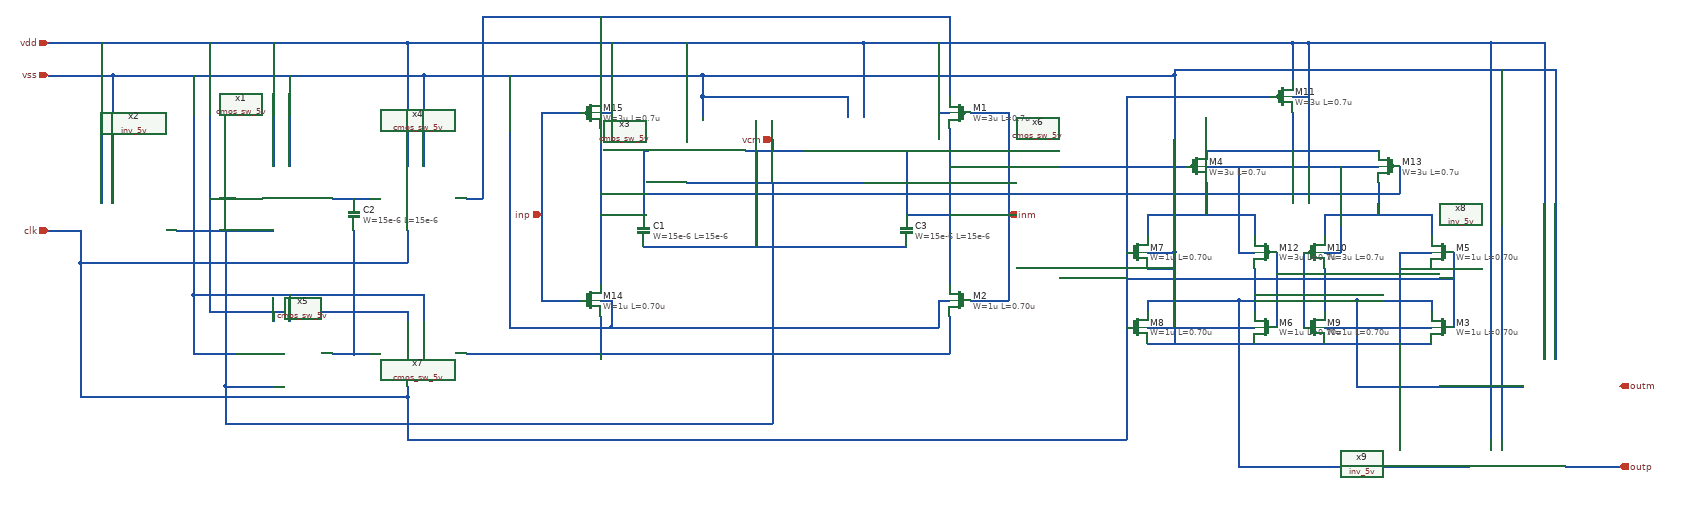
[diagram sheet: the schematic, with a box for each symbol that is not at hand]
v {xschem version=3.4.5 file_version=1.2
}
G {}
K {}
V {}
S {}
E {}
N -1310 -180 -1240 -180 {
lab=#net1}
N -1310 110 -1270 110 {
lab=#net2}
N -1270 110 -1240 110 {
lab=#net2}
N -1720 -470 -1170 -470 {
lab=vdd}
N -1170 -470 -1170 -240 {
lab=vdd}
N -1420 -470 -1420 -240 {
lab=vdd}
N -1720 -410 -1140 -410 {
lab=vss}
N -1140 -410 -1140 -240 {
lab=vss}
N -1390 -410 -1390 -240 {
lab=vss}
N -1170 30 -1170 50 {
lab=vdd}
N -1540 30 -1170 30 {
lab=vdd}
N -1540 -470 -1540 30 {
lab=vdd}
N -1140 0 -1140 50 {
lab=vss}
N -1570 0 -1140 0 {
lab=vss}
N -1570 -410 -1570 0 {
lab=vss}
N -1390 0 -1390 50 {
lab=vss}
N -1420 30 -1420 50 {
lab=vdd}
N -1540 -180 -1490 -180 {
lab=vdd}
N -1570 0 -1570 110 {
lab=vss}
N -1570 110 -1490 110 {
lab=vss}
N -1270 -120 -1270 110 {
lab=#net2}
N -1600 -120 -1420 -120 {
lab=#net3}
N -1510 -120 -1510 170 {
lab=#net3}
N -1510 170 -1420 170 {
lab=#net3}
N -1170 -120 -1170 -60 {
lab=clk}
N -1780 -60 -1170 -60 {
lab=clk}
N -1780 -120 -1780 -60 {
lab=clk}
N -1170 170 -1170 190 {
lab=clk}
N -1780 190 -1170 190 {
lab=clk}
N -1780 -60 -1780 190 {
lab=clk}
N -1840 -120 -1780 -120 {
lab=clk}
N -1840 -410 -1720 -410 {
lab=vss}
N -1830 -470 -1720 -470 {
lab=vdd}
N -1840 -470 -1830 -470 {
lab=vdd}
N -810 -340 -790 -340 {
lab=vdd}
N -790 -390 -790 -340 {
lab=vdd}
N -810 40 -810 80 {
lab=#net4}
N -810 10 -790 10 {
lab=vss}
N -790 10 -790 60 {
lab=vss}
N -810 -310 -810 -20 {
lab=#net5}
N -810 -150 -730 -150 {
lab=#net5}
N -730 -270 -720 -270 {
lab=#net5}
N -730 -270 -730 -150 {
lab=#net5}
N -920 -340 -920 -150 {
lab=inp}
N -920 -340 -850 -340 {
lab=inp}
N -920 -150 -920 10 {
lab=inp}
N -920 10 -850 10 {
lab=inp}
N -540 -270 -430 -270 {
lab=vcm}
N -490 -290 -490 -270 {
lab=vcm}
N -650 -210 -360 -210 {
lab=#net3}
N -1510 170 -1510 240 {
lab=#net3}
N -1510 240 -490 240 {
lab=#net3}
N -490 -200 -490 240 {
lab=#net3}
N -490 -210 -490 -200 {
lab=#net3}
N -180 -340 -160 -340 {
lab=vdd}
N -160 40 -160 80 {
lab=#net4}
N -180 10 -160 10 {
lab=vss}
N -180 10 -180 60 {
lab=vss}
N -160 -310 -160 -20 {
lab=#net6}
N -240 -150 -160 -150 {
lab=#net6}
N -250 -270 -240 -270 {
lab=#net6}
N -240 -270 -240 -150 {
lab=#net6}
N -50 -340 -50 -150 {
lab=inm}
N -120 -340 -50 -340 {
lab=inm}
N -50 -150 -50 10 {
lab=inm}
N -120 10 -50 10 {
lab=inm}
N -360 -210 -320 -210 {
lab=#net3}
N -350 -370 -350 -330 {
lab=vss}
N -620 -370 -350 -370 {
lab=vss}
N -620 -370 -620 -330 {
lab=vss}
N -1170 -470 -320 -470 {
lab=vdd}
N -320 -470 -320 -330 {
lab=vdd}
N -650 -470 -650 -330 {
lab=vdd}
N -1140 -410 -620 -410 {
lab=vss}
N -620 -410 -620 -370 {
lab=vss}
N -730 -90 -240 -90 {
lab=vcm}
N -520 -270 -520 -90 {
lab=vcm}
N -810 -390 -810 -370 {
lab=#net7}
N -160 -520 -160 -370 {
lab=#net7}
N -1030 -520 -160 -520 {
lab=#net7}
N -1030 -520 -1030 -180 {
lab=#net7}
N -1060 -180 -1030 -180 {
lab=#net7}
N -810 -520 -810 -390 {
lab=#net7}
N -1060 110 -160 110 {
lab=#net4}
N -160 80 -160 110 {
lab=#net4}
N -810 80 -810 110 {
lab=#net4}
N 210 90 740 90 {
lab=vss}
N 210 60 410 60 {
lab=vss}
N 540 60 740 60 {
lab=vss}
N 680 60 680 90 {
lab=vss}
N 680 -80 680 60 {
lab=vss}
N 680 -80 740 -80 {
lab=vss}
N 680 -50 740 -50 {
lab=vss}
N 210 -80 260 -80 {
lab=vss}
N 260 -80 260 90 {
lab=vss}
N 210 -50 260 -50 {
lab=vss}
N 260 60 260 90 {
lab=vss}
N 450 -80 450 60 {
lab=#net8}
N 410 -50 410 30 {
lab=#net9}
N 500 -80 500 60 {
lab=#net9}
N 540 -50 540 30 {
lab=#net8}
N 450 -40 540 -40 {
lab=#net8}
N 410 0 500 0 {
lab=#net9}
N 210 -150 210 -110 {
lab=#net10}
N 410 -140 410 -110 {
lab=#net10}
N 210 -150 410 -150 {
lab=#net10}
N 410 -150 410 -140 {
lab=#net10}
N 320 -210 320 -150 {
lab=#net10}
N 740 -150 740 -110 {
lab=#net11}
N 540 -150 740 -150 {
lab=#net11}
N 540 -150 540 -110 {
lab=#net11}
N 640 -210 640 -150 {
lab=#net11}
N 320 -270 640 -270 {
lab=#net12}
N 480 -340 480 -270 {
lab=#net12}
N -320 -470 470 -470 {
lab=vdd}
N 470 -470 480 -470 {
lab=vdd}
N 480 -470 480 -400 {
lab=vdd}
N 320 -240 640 -240 {
lab=vdd}
N 380 -80 410 -80 {
lab=vdd}
N 380 -240 380 -80 {
lab=vdd}
N 540 -80 570 -80 {
lab=vdd}
N 570 -240 570 -80 {
lab=vdd}
N 510 -470 510 -240 {
lab=vdd}
N 480 -470 510 -470 {
lab=vdd}
N 480 -370 510 -370 {
lab=vdd}
N -160 -240 280 -240 {
lab=#net6}
N 680 -240 680 -190 {
lab=#net5}
N -810 -190 680 -190 {
lab=#net5}
N 170 -80 170 60 {
lab=clk}
N 780 -80 780 60 {
lab=clk}
N 170 -30 780 -30 {
lab=clk}
N 170 -370 440 -370 {
lab=clk}
N 170 -370 170 -80 {
lab=clk}
N 170 60 170 270 {
lab=clk}
N -1170 270 170 270 {
lab=clk}
N -1170 190 -1170 270 {
lab=clk}
N 260 -410 260 -80 {
lab=vss}
N -620 -410 260 -410 {
lab=vss}
N 380 10 380 160 {
lab=#net9}
N 380 10 410 10 {
lab=#net9}
N 540 10 600 10 {
lab=#net8}
N 600 10 600 160 {
lab=#net8}
N 210 10 210 30 {
lab=#net9}
N 210 10 380 10 {
lab=#net9}
N 740 10 740 30 {
lab=#net8}
N 600 10 740 10 {
lab=#net8}
N -1740 -470 -1740 -170 {
lab=vdd}
N -1720 -410 -1720 -170 {
lab=vss}
N 990 320 1090 320 {
lab=outp}
N 380 320 810 320 {
lab=#net9}
N 380 160 380 320 {
lab=#net9}
N 600 160 600 170 {
lab=#net8}
N 600 170 910 170 {
lab=#net8}
N 850 -470 850 270 {
lab=vdd}
N 510 -470 850 -470 {
lab=vdd}
N 850 -470 950 -470 {
lab=vdd}
N 950 -470 950 120 {
lab=vdd}
N 970 -420 970 120 {
lab=vss}
N 260 -420 970 -420 {
lab=vss}
N 260 -420 260 -410 {
lab=vss}
N 870 -420 870 270 {
lab=vss}
N -790 -470 -790 -390 {
lab=vdd}
N -180 -470 -180 -340 {
lab=vdd}
N -790 60 -180 60 {
lab=vss}
N -980 60 -790 60 {
lab=vss}
N -980 -410 -980 60 {
lab=vss}
C {cmos_sw_5v.sym} -1400 -180 0 0 {name=x1}
C {inv_5v.sym} -1690 -120 0 0 {name=x2}
C {devices/iopin.sym} -1840 -410 2 0 {name=p5 lab=vss}
C {devices/ipin.sym} -1840 -120 0 0 {name=p1 lab=clk}
C {devices/ipin.sym} -920 -150 0 0 {name=p6 lab=inp}
C {devices/iopin.sym} -490 -290 3 0 {name=p2 lab=vcm}
C {devices/ipin.sym} -50 -150 0 1 {name=p3 lab=inm}
C {devices/opin.sym} 1090 320 0 0 {name=p7 lab=outp}
C {devices/opin.sym} 1090 170 0 0 {name=p8 lab=outm}
C {devices/iopin.sym} -1840 -470 2 0 {name=p9 lab=vdd}
C {symbols/cap_mim_2p0fF.sym} -1270 -150 0 0 {name=C2
W=15e-6
L=15e-6
model=cap_mim_2f0fF
spiceprefix=X
m=1}
C {symbols/nfet_05v0.sym} -830 10 0 0 {name=M14
L=0.70u
W=1u
nf=1
m=1
ad="'int((nf+1)/2) * W/nf * 0.18u'"
pd="'2*int((nf+1)/2) * (W/nf + 0.18u)'"
as="'int((nf+2)/2) * W/nf * 0.18u'"
ps="'2*int((nf+2)/2) * (W/nf + 0.18u)'"
nrd="'0.18u / W'" nrs="'0.18u / W'"
sa=0 sb=0 sd=0
model=nfet_06v0
spiceprefix=X
}
C {symbols/pfet_06v0.sym} -830 -340 0 0 {name=M15
L=0.7u
W=3u
nf=1
m=1
ad="'int((nf+1)/2) * W/nf * 0.18u'"
pd="'2*int((nf+1)/2) * (W/nf + 0.18u)'"
as="'int((nf+2)/2) * W/nf * 0.18u'"
ps="'2*int((nf+2)/2) * (W/nf + 0.18u)'"
nrd="'0.18u / W'" nrs="'0.18u / W'"
sa=0 sb=0 sd=0
model=pfet_05v0
spiceprefix=X
}
C {cmos_sw_5v.sym} -1150 -180 0 0 {name=x4}
C {cmos_sw_5v.sym} -1400 110 0 0 {name=x5}
C {cmos_sw_5v.sym} -1150 110 0 0 {name=x7}
C {cmos_sw_5v.sym} -630 -270 0 0 {name=x3}
C {cmos_sw_5v.sym} -340 -270 0 1 {name=x6}
C {inv_5v.sym} 1000 170 0 0 {name=x8}
C {inv_5v.sym} 900 320 0 0 {name=x9}
C {symbols/pfet_06v0.sym} -140 -340 0 1 {name=M1
L=0.7u
W=3u
nf=1
m=1
ad="'int((nf+1)/2) * W/nf * 0.18u'"
pd="'2*int((nf+1)/2) * (W/nf + 0.18u)'"
as="'int((nf+2)/2) * W/nf * 0.18u'"
ps="'2*int((nf+2)/2) * (W/nf + 0.18u)'"
nrd="'0.18u / W'" nrs="'0.18u / W'"
sa=0 sb=0 sd=0
model=pfet_05v0
spiceprefix=X
}
C {symbols/nfet_05v0.sym} -140 10 0 1 {name=M2
L=0.70u
W=1u
nf=1
m=1
ad="'int((nf+1)/2) * W/nf * 0.18u'"
pd="'2*int((nf+1)/2) * (W/nf + 0.18u)'"
as="'int((nf+2)/2) * W/nf * 0.18u'"
ps="'2*int((nf+2)/2) * (W/nf + 0.18u)'"
nrd="'0.18u / W'" nrs="'0.18u / W'"
sa=0 sb=0 sd=0
model=nfet_06v0
spiceprefix=X
}
C {symbols/nfet_05v0.sym} 760 60 0 1 {name=M3
L=0.70u
W=1u
nf=1
m=1
ad="'int((nf+1)/2) * W/nf * 0.18u'"
pd="'2*int((nf+1)/2) * (W/nf + 0.18u)'"
as="'int((nf+2)/2) * W/nf * 0.18u'"
ps="'2*int((nf+2)/2) * (W/nf + 0.18u)'"
nrd="'0.18u / W'" nrs="'0.18u / W'"
sa=0 sb=0 sd=0
model=nfet_06v0
spiceprefix=X
}
C {symbols/nfet_05v0.sym} 760 -80 0 1 {name=M5
L=0.70u
W=1u
nf=1
m=1
ad="'int((nf+1)/2) * W/nf * 0.18u'"
pd="'2*int((nf+1)/2) * (W/nf + 0.18u)'"
as="'int((nf+2)/2) * W/nf * 0.18u'"
ps="'2*int((nf+2)/2) * (W/nf + 0.18u)'"
nrd="'0.18u / W'" nrs="'0.18u / W'"
sa=0 sb=0 sd=0
model=nfet_06v0
spiceprefix=X
}
C {symbols/nfet_05v0.sym} 430 60 0 1 {name=M6
L=0.70u
W=1u
nf=1
m=1
ad="'int((nf+1)/2) * W/nf * 0.18u'"
pd="'2*int((nf+1)/2) * (W/nf + 0.18u)'"
as="'int((nf+2)/2) * W/nf * 0.18u'"
ps="'2*int((nf+2)/2) * (W/nf + 0.18u)'"
nrd="'0.18u / W'" nrs="'0.18u / W'"
sa=0 sb=0 sd=0
model=nfet_06v0
spiceprefix=X
}
C {symbols/nfet_05v0.sym} 190 -80 0 0 {name=M7
L=0.70u
W=1u
nf=1
m=1
ad="'int((nf+1)/2) * W/nf * 0.18u'"
pd="'2*int((nf+1)/2) * (W/nf + 0.18u)'"
as="'int((nf+2)/2) * W/nf * 0.18u'"
ps="'2*int((nf+2)/2) * (W/nf + 0.18u)'"
nrd="'0.18u / W'" nrs="'0.18u / W'"
sa=0 sb=0 sd=0
model=nfet_06v0
spiceprefix=X
}
C {symbols/nfet_05v0.sym} 190 60 0 0 {name=M8
L=0.70u
W=1u
nf=1
m=1
ad="'int((nf+1)/2) * W/nf * 0.18u'"
pd="'2*int((nf+1)/2) * (W/nf + 0.18u)'"
as="'int((nf+2)/2) * W/nf * 0.18u'"
ps="'2*int((nf+2)/2) * (W/nf + 0.18u)'"
nrd="'0.18u / W'" nrs="'0.18u / W'"
sa=0 sb=0 sd=0
model=nfet_06v0
spiceprefix=X
}
C {symbols/nfet_05v0.sym} 520 60 0 0 {name=M9
L=0.70u
W=1u
nf=1
m=1
ad="'int((nf+1)/2) * W/nf * 0.18u'"
pd="'2*int((nf+1)/2) * (W/nf + 0.18u)'"
as="'int((nf+2)/2) * W/nf * 0.18u'"
ps="'2*int((nf+2)/2) * (W/nf + 0.18u)'"
nrd="'0.18u / W'" nrs="'0.18u / W'"
sa=0 sb=0 sd=0
model=nfet_06v0
spiceprefix=X
}
C {symbols/pfet_06v0.sym} 460 -370 0 0 {name=M11
L=0.7u
W=3u
nf=1
m=1
ad="'int((nf+1)/2) * W/nf * 0.18u'"
pd="'2*int((nf+1)/2) * (W/nf + 0.18u)'"
as="'int((nf+2)/2) * W/nf * 0.18u'"
ps="'2*int((nf+2)/2) * (W/nf + 0.18u)'"
nrd="'0.18u / W'" nrs="'0.18u / W'"
sa=0 sb=0 sd=0
model=pfet_05v0
spiceprefix=X
}
C {symbols/cap_mim_2p0fF.sym} -730 -120 0 0 {name=C1
W=15e-6
L=15e-6
model=cap_mim_2f0fF
spiceprefix=X
m=1}
C {symbols/cap_mim_2p0fF.sym} -240 -120 0 0 {name=C3
W=15e-6
L=15e-6
model=cap_mim_2f0fF
spiceprefix=X
m=1}
C {symbols/pfet_06v0.sym} 300 -240 0 0 {name=M4
L=0.7u
W=3u
nf=1
m=1
ad="'int((nf+1)/2) * W/nf * 0.18u'"
pd="'2*int((nf+1)/2) * (W/nf + 0.18u)'"
as="'int((nf+2)/2) * W/nf * 0.18u'"
ps="'2*int((nf+2)/2) * (W/nf + 0.18u)'"
nrd="'0.18u / W'" nrs="'0.18u / W'"
sa=0 sb=0 sd=0
model=pfet_05v0
spiceprefix=X
}
C {symbols/pfet_06v0.sym} 520 -80 0 0 {name=M10
L=0.7u
W=3u
nf=1
m=1
ad="'int((nf+1)/2) * W/nf * 0.18u'"
pd="'2*int((nf+1)/2) * (W/nf + 0.18u)'"
as="'int((nf+2)/2) * W/nf * 0.18u'"
ps="'2*int((nf+2)/2) * (W/nf + 0.18u)'"
nrd="'0.18u / W'" nrs="'0.18u / W'"
sa=0 sb=0 sd=0
model=pfet_05v0
spiceprefix=X
}
C {symbols/pfet_06v0.sym} 430 -80 0 1 {name=M12
L=0.7u
W=3u
nf=1
m=1
ad="'int((nf+1)/2) * W/nf * 0.18u'"
pd="'2*int((nf+1)/2) * (W/nf + 0.18u)'"
as="'int((nf+2)/2) * W/nf * 0.18u'"
ps="'2*int((nf+2)/2) * (W/nf + 0.18u)'"
nrd="'0.18u / W'" nrs="'0.18u / W'"
sa=0 sb=0 sd=0
model=pfet_05v0
spiceprefix=X
}
C {symbols/pfet_06v0.sym} 660 -240 0 1 {name=M13
L=0.7u
W=3u
nf=1
m=1
ad="'int((nf+1)/2) * W/nf * 0.18u'"
pd="'2*int((nf+1)/2) * (W/nf + 0.18u)'"
as="'int((nf+2)/2) * W/nf * 0.18u'"
ps="'2*int((nf+2)/2) * (W/nf + 0.18u)'"
nrd="'0.18u / W'" nrs="'0.18u / W'"
sa=0 sb=0 sd=0
model=pfet_05v0
spiceprefix=X
}
